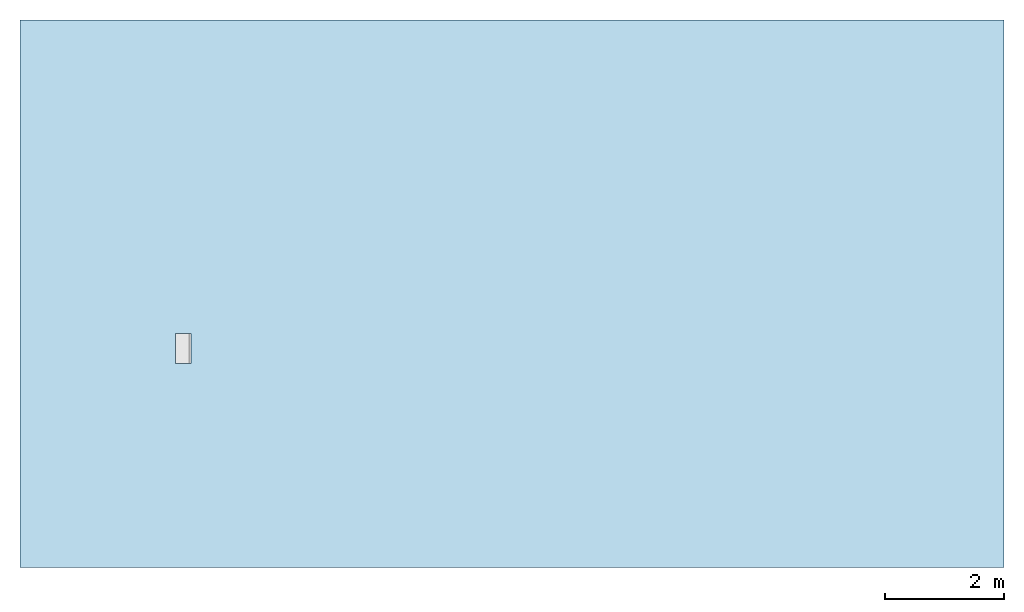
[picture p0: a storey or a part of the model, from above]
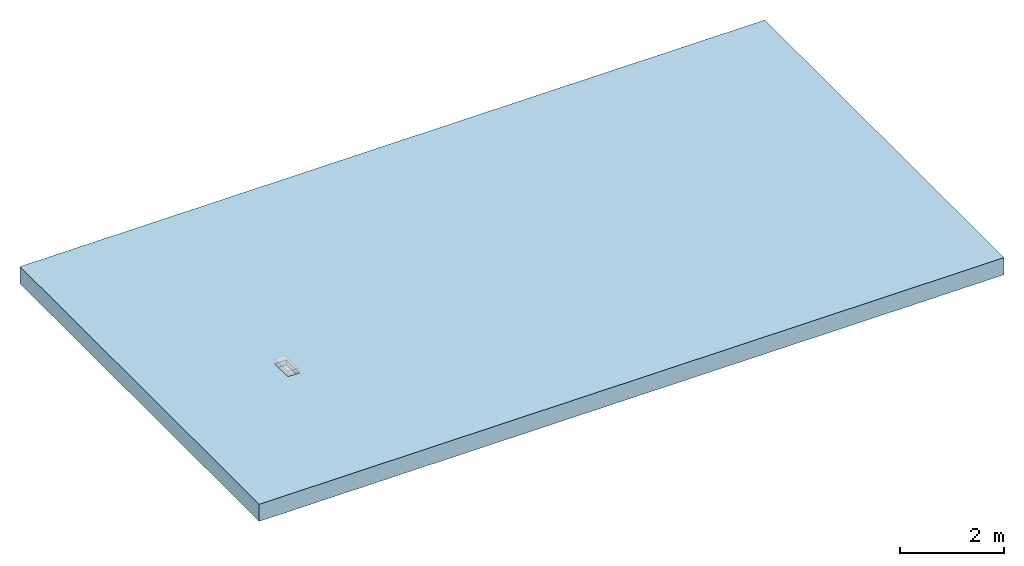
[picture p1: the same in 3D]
Properties of the parts of a building model (IFC2X3)

# File
Description: ViewDefinition [CoordinationView]
File name: T0133 - Blind Channel - 500mm LG - 235mm High.ifc
Time: 2013-09-04T09:03:15
Written by: Autodesk Revit 2013
Made in: 20120221_2030(x64)

# IfcProject, Project Number
LongName: Project Name; Phase: Project Status

# IfcSite, Default
RefLatitude: 42, 21, 30, 344238; RefLongitude: -71, -3, -35, -194702; RefElevation: 0 mm

# IfcBuilding
Pset_BuildingCommon - NumberOfStoreys: 1
Other - Project Address: ## Street City, State Zip; Project Number: Project Number; Client Name: Owner; Project Name: Project Name; Project Issue Date: Issue Date; Project Status: Project Status

# IfcBuildingStorey, Level 1
LongName: Level 1; Elevation: 0 mm
Constraints - Elevation Base: 0; Elevation: 0 mm
Graphics - Line Weight: 1; Line Pattern: Center; Symbol at End 2 Default: yes; Symbol at End 1 Default: no; Color: 0; Symbol: M_Level Head - Circle: M_Level Head - Circle
Identity Data - Structural: no; Building Story: yes; Name: Level 1
Dimensions - Computation Height: 0 mm

# IfcBuildingElementProxy: T0133 - Blind Channel - 500mm LG - 235mm High, Civil-Drainage-Channel-ACO-KerbDrain-KD200:T0133 - Blind Channel - 500mm LG - 235mm High:T0133 - Blind Channel - 500mm LG - 235mm High:308203
In: Level 1
Material: ACO Polymer Concrete.
Phasing - Phase Created: New Construction
Constraints - Moves With Nearby Elements: no; Level: Level: Level 1
Dimensions - Volume: 19149618 mm3; Void length: 500 mm; Void Depth.: -110 mm
Pset_BuildingElementProxyCommon - Reference: T0133 - Blind Channel - 500mm LG - 235mm High
Materials and Finishes - End Cap Colour: N/A; Channel Colour: Grey; Access Cover/Frame Material: N/A; End Cap Material: N/A; Channel Material: Vienite® Synthetic Resin Concrete; Access Cover/Frame Colour: N/A; Access Cover/Frame Finish: N/A
Green Building Properties - Channel Recycled Material Content: 20% minimum; Channel Recyclable: Fully recyclable; Access Cover/Frame Recyclable: N/A; End Cap Recycled Material Content: N/A; End Cap Recyclable: N/A; Access Cover/Frame Recycled Material Content: N/A
Identity Data - Installation guidelines: http://www.aco.co.uk/download.php?id=120; Product Code: T0133; Maintenance guidelines: http://www.aco.co.uk/download.php?id=120; Type Comments: ACO KerbDrain KD200 half battered blind kerb unit 235 high 500mm long; Price: POA - contact ACO; Assembly Description: Rain Water Drainage; Cost: 0; Fax: +44 (0)1462 815895; OmniClass Title: Rainwater Removal; e-mail Sales: customersupport@aco.co.uk; Product brochure: http://www.aco.co.uk/download.php?id=120; Manufacturer: ACO Technologies plc - ACO Water Management Division; URL: www.aco.co.uk; Model: ACO KerbDrain KD200; Assembly Code: D2040; OmniClass Number: 23.70.50.24; Model Description: Combined kerb and drainage system; Telephone: +44 (0)1462 816666; Product Page URL: http://www.aco.co.uk/product_detail.php?id=3; e-mail Technical: technical@aco.co.uk; Address: ACO Business Park, Hitchin Road, Shefford, Bedfordshire, United Kingdom SG17 5TE
Data - Channel C.S.A: 0.02m²; Drainage Slot Intake area: N/A; Concrete Surround Volume - Load Class A 15 - D 400 - Concrete Pavement: 0.20m³/m; Installation - Concrete Grade: Refer to brochure; Product Dimensions: 500mm x 260mm x 235mm (LxWxH); Invert Depth: 205mm; Product Weight: 41.9 Kg; Hydraulic Performance: http://www.aco.co.uk/download.php?id=120; ACO Hydraulic Design Software: http://www.acodesign.co.uk; Load Class: A 15 - D 400 A 15 - D 400; Drainage Slot Width: N/A; Product Standard: BS EN 1433:2002, CE marked, Kitemarked
Construction - Blindunit_220: no; Accessunit_220: no; Access Cover: no; Channelunit_220: no; Closing end cap: no; Channelunit_235: no; Blindunit_235: yes; Accessunit_235: no
General - SerialNumber: 0.000000; TagNumber: 0.000000
Other - CreatedBy: www.aco.co.uk; Revision: 1

# IfcOpeningElement: Recess
In: Level 1
Constraints - Related to Mass: no; Height Offset From Level: 0 mm; Room Bounding: yes; Level: Level: Level 1
Dimensions - Perimeter: 51360 mm; Thickness: 400 mm; Volume: 60573700000 mm3; Area: 151470000 mm2
Structural - Enable Analytical Model: no; Structural: no
Phasing - Phase Created: New Construction
Construction - Default Thickness: 400 mm; Function: 0
Graphics - Coarse Scale Fill Color: 0
Analytical Properties - Absorptance: 0.1; Roughness: 1
Materials and Finishes - Structural Material: Plant

# IfcSlab: Floor:Generic Floor - 400mm, Floor:Generic Floor - 400mm:193825
In: Level 1
PredefinedType: FLOOR; Material: Plant 400 mm
Constraints - Related to Mass: no; Height Offset From Level: 0 mm; Room Bounding: yes; Level: Level: Level 1
Dimensions - Perimeter: 51360 mm; Thickness: 400 mm; Volume: 60573700000 mm3; Area: 151470000 mm2
Structural - Enable Analytical Model: no; Structural: no
Phasing - Phase Created: New Construction
Pset_SlabCommon - Reference: Generic Floor - 400mm; IsExternal: no; LoadBearing: yes
Construction - Default Thickness: 400 mm; Function: 0
Graphics - Coarse Scale Fill Color: 0
Analytical Properties - Absorptance: 0.1; Roughness: 1
Materials and Finishes - Structural Material: Plant
